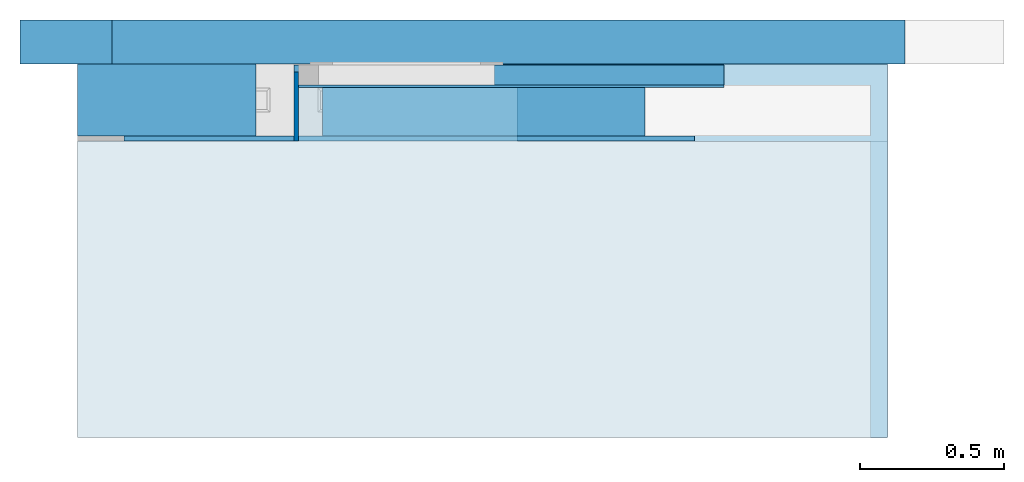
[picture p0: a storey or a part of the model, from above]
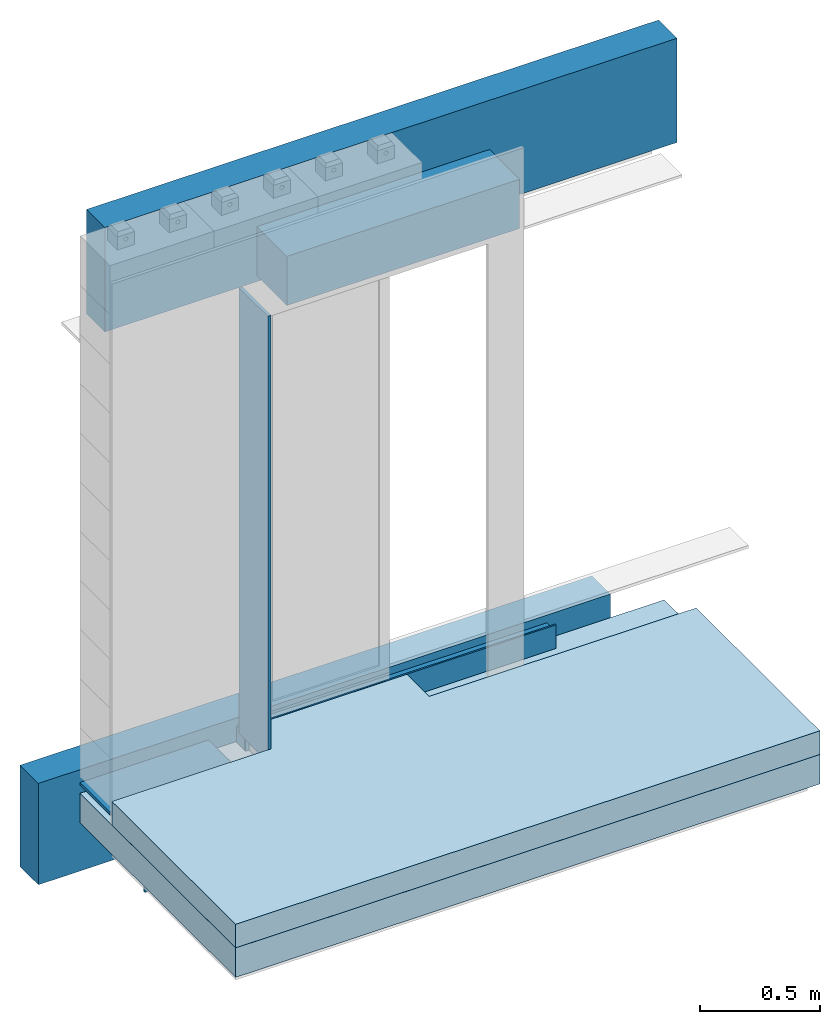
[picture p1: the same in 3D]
Properties of the parts of a building model (IFC4)

# File
Description: ViewDefinition [ReferenceView_V1.2], RevitIdentifiers [ContentGUID: d45b1106-0c7a-46e1-869b-c6a7bbcc7ea5, VersionGUID: 118b0530-1591-4ac2-8939-a10ffb714872, NumberOfSaves: 70], CoordinateReference [CoordinateBase: Internal Origin, ProjectSite: Internal], ExchangeRequirement [Architecture]
File name: 3dv__Detail__15__212, WS25, Door, F90, Vertical_WIP Copy 1.ifc
Time: 2025-12-19T14:29:21+01:00
Written by: ODA SDAI 25.12
Made in: Autodesk - Revit 26.3.0.37 (ENU) - 26.4.1.0

# IfcSite, Default
RefLatitude: 45, 45, 37, 23925; RefLongitude: 21, 14, 26, 780090; RefElevation: 0 cm

# IfcBuildingStorey (10)
Name | LongName | Elevation (cm)
B2__ABOVE Slab | B2__ABOVE Slab | -612
B1__ABOVE Slab | B1__ABOVE Slab | -312
L00__ABOVE Slab | L00__ABOVE Slab | -12
L01__ABOVE Slab | L01__ABOVE Slab | 273
L02__ABOVE Slab | L02__ABOVE Slab | 558
L03__ABOVE Slab | L03__ABOVE Slab | 843
L04__ABOVE Slab | L04__ABOVE Slab | 1128
L05__ABOVE Slab | L05__ABOVE Slab | 1413
L06__ABOVE Slab | L06__ABOVE Slab | 1698
L07__ABOVE Slab | L07__ABOVE Slab | 1983

# IfcBeam: Structural Framing : sfr__WOOD__Rectangular__sf : 15 x 1cm
In: L00__ABOVE Slab
Type - PredefinedType: BEAM; Material: _STRUCTURE__Wood
Classification: III-3 (Uniformat)

# IfcBeam: Structural Framing : sfr__WOOD__Rectangular__sf : 15 x 25cm
In: L00__ABOVE Slab
Type - PredefinedType: BEAM; Material: _MASONRY__Timber Block__Triqbriq, Filler
Classification: III-3 (Uniformat)

# IfcColumn: Columns : wll__TIMBER CORE__Triqbriq__lb : WS25 (3)
Type - PredefinedType: COLUMN; Material: <Unnamed>
Name (Columns : wll__TIMBER CORE__Triqbriq__lb :...) | In
2 x  WS25 | L00__ABOVE Slab
 WS25 | B1__ABOVE Slab

# IfcColumn: Columns : wll_s__TIMBER BLOCK__Triqbriq, Full Width__wp : WS25 (16)
Type - PredefinedType: COLUMN; Material: _MASONRY__Timber Block__Triqbriq, X, _MASONRY__Timber Block__Triqbriq, Y
Name (Columns : wll_s__TIMBER BLOCK__Triqbriq, Full Width__wp :...) | In
13 x  WS25 | L00__ABOVE Slab
3 x  WS25 | B1__ABOVE Slab

# IfcColumn: Columns : wll_s__TIMBER BLOCK__Triqbriq, Half Width__wp : WS25 (10)
In: L00__ABOVE Slab
Type - PredefinedType: COLUMN; Material: _MASONRY__Timber Block__Triqbriq, X, _MASONRY__Timber Block__Triqbriq, Y

# IfcCovering: Ceilings : Compound Ceiling : clg__INT COVERING__, GB 1.5cm__12.5(A) 3 (2)
In: L00__ABOVE Slab
Type - PredefinedType: CEILING
Classification: A 6.1.2.1 Plafoane gips-carton, placi cu cerinte standard (Uniformat); Material: _WLL & CLG FINISHES__Lime - CEM Plaster

# IfcCovering: Ceilings : Compound Ceiling : clg__INT COVERING__Wood (2)
In: L00__ABOVE Slab
Type - PredefinedType: CEILING
Classification: A 6.1.2.1 Plafoane gips-carton, placi cu cerinte standard (Uniformat); Material: _STRUCTURE__Wood Solid

# IfcOpeningElement, Walls : Basic Wall : wll__INT FINISH__Spritzkork, Lime - CEM Plaster 2.4cm TRIQBRIQ
In: L00__ABOVE Slab
PredefinedType: OPENING

# IfcSlab: Floors : Floor : flr__INT COVERING__Parquet
In: L00__ABOVE Slab
Type - PredefinedType: FLOOR; Material: _FINISH STAIR__Int__Parquet Flooring__Stairs, _FLR LAYERS__Screed, SL 0.5%__Semi-dry CEM, Rc ≥ 22.5 N/mm², _FLR COVERING__Polished Concrete, _FCD VENT LAYERS__Support Board__OSB 3
Classification: A 8.1.1.2 Pardoseli epoxidice si poliuretanice (Uniformat)

# IfcSlab: Floors : Floor : flr__STRUCTURE__Wood Beams 15cm__TriqBriq
In: L00__ABOVE Slab
Type - PredefinedType: FLOOR; Material: _STRUCTURE__Wood
Classification: S 1.2 Plansee si acoperisuri terasa (Uniformat)

# IfcWall: Walls : Basic Wall : wll__EXT ENCLOSURE__Spritzkork, Wood Insulation 8.4cm__TriqBriq, FS.1 (2)
In: L00__ABOVE Slab
Type - PredefinedType: STANDARD; Material: _FCD FINISH__Mineral Render__Combed, H L/O__Capatect Kreativeffekt "Filigrano"__White, _STRUCTURE__Wood Solid, _FCD LAYERS__Insulation__Wood-fiber__Steico
Classification: A 4.3.4.2.1 Pereti exteriori (Uniformat)

# IfcWall: Walls : Basic Wall : wll__INT FINISH__Lime - CEM Plaster 4cm 3
In: L00__ABOVE Slab
Type - PredefinedType: STANDARD; Material: _WLL & CLG FINISHES__Lime - CEM Plaster
Classification: A 7.1.1 Tencuieli umede (Uniformat)

# IfcWall: Walls : Basic Wall : wll__INT FINISH__Spritzkork, Lime - CEM Plaster 2.4cm TRIQBRIQ (3)
In: L00__ABOVE Slab
Type - PredefinedType: STANDARD; Material: _WLL & CLG FINISHES__Lime - CEM Plaster, _FCD LAYERS__Insulation__EPS 120__Austrotherm EPS A120
Classification: A 7.1.1 Tencuieli umede (Uniformat)

# IfcWall: Walls : Basic Wall : wll__UNCLASSIFIED__Randdämmstreifen 1.5cm
In: L00__ABOVE Slab
Type - PredefinedType: STANDARD; Material: _FCD LAYERS__Insulation__EPS 120__Austrotherm EPS A120
Classification: N NECLASIFICAT (Uniformat)

# IfcWindow: Windows : wdw_s__PANEL__Mobile, Hung, Interior__wp : Glazed, Bottom&side hung
In: L00__ABOVE Slab
Type - PredefinedType: WINDOW; Material: Miscellaneous_Profile_Aluminium, Unassigned_Glazing
OverallHeight: 98 cm; OverallWidth: 72 cm

# IfcWindow: Windows : wdw_s__PROFILE__Frame__wp : Wood (3)
In: L00__ABOVE Slab
Type - PredefinedType: WINDOW; Material: _WINDOW__Profile__Aluminium
OverallHeight: 28.3557 cm; OverallWidth: 7 cm
